VERSION 5.7 ;
BUSBITCHARS "[]" ;
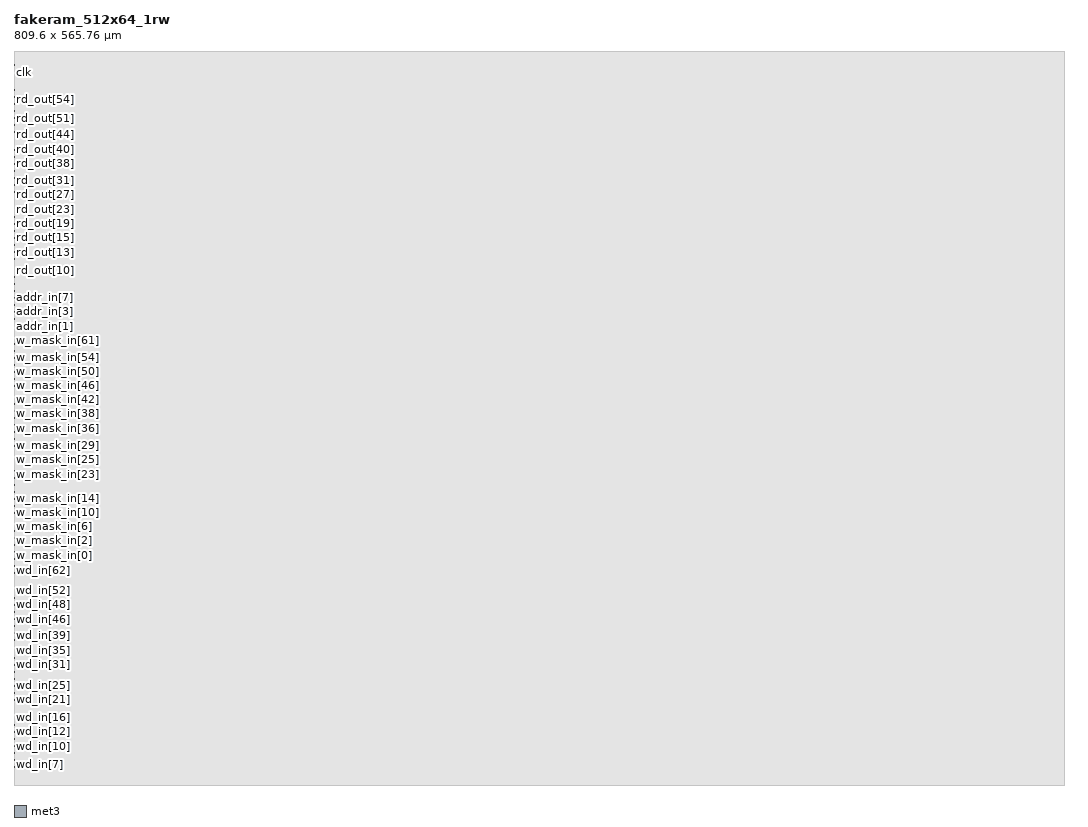
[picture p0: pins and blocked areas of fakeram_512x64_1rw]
MACRO fakeram_512x64_1rw
  FOREIGN fakeram_512x64_1rw 0 0 ;
  SYMMETRY X Y R90 ;
  SIZE 809.600 BY 565.760 ;
  CLASS BLOCK ;
  PIN wd_in[0]
    DIRECTION INPUT ;
    USE SIGNAL ;
    SHAPE ABUTMENT ;
    PORT
      LAYER met3 ;
      RECT 0.000 2.720 0.300 3.020 ;
    END
  END wd_in[0]
  PIN wd_in[1]
    DIRECTION INPUT ;
    USE SIGNAL ;
    SHAPE ABUTMENT ;
    PORT
      LAYER met3 ;
      RECT 0.000 5.440 0.300 5.740 ;
    END
  END wd_in[1]
  PIN wd_in[2]
    DIRECTION INPUT ;
    USE SIGNAL ;
    SHAPE ABUTMENT ;
    PORT
      LAYER met3 ;
      RECT 0.000 8.160 0.300 8.460 ;
    END
  END wd_in[2]
  PIN wd_in[3]
    DIRECTION INPUT ;
    USE SIGNAL ;
    SHAPE ABUTMENT ;
    PORT
      LAYER met3 ;
      RECT 0.000 10.880 0.300 11.180 ;
    END
  END wd_in[3]
  PIN wd_in[4]
    DIRECTION INPUT ;
    USE SIGNAL ;
    SHAPE ABUTMENT ;
    PORT
      LAYER met3 ;
      RECT 0.000 13.600 0.300 13.900 ;
    END
  END wd_in[4]
  PIN wd_in[5]
    DIRECTION INPUT ;
    USE SIGNAL ;
    SHAPE ABUTMENT ;
    PORT
      LAYER met3 ;
      RECT 0.000 16.320 0.300 16.620 ;
    END
  END wd_in[5]
  PIN wd_in[6]
    DIRECTION INPUT ;
    USE SIGNAL ;
    SHAPE ABUTMENT ;
    PORT
      LAYER met3 ;
      RECT 0.000 19.040 0.300 19.340 ;
    END
  END wd_in[6]
  PIN wd_in[7]
    DIRECTION INPUT ;
    USE SIGNAL ;
    SHAPE ABUTMENT ;
    PORT
      LAYER met3 ;
      RECT 0.000 21.760 0.300 22.060 ;
    END
  END wd_in[7]
  PIN wd_in[8]
    DIRECTION INPUT ;
    USE SIGNAL ;
    SHAPE ABUTMENT ;
    PORT
      LAYER met3 ;
      RECT 0.000 24.480 0.300 24.780 ;
    END
  END wd_in[8]
  PIN wd_in[9]
    DIRECTION INPUT ;
    USE SIGNAL ;
    SHAPE ABUTMENT ;
    PORT
      LAYER met3 ;
      RECT 0.000 27.200 0.300 27.500 ;
    END
  END wd_in[9]
  PIN wd_in[10]
    DIRECTION INPUT ;
    USE SIGNAL ;
    SHAPE ABUTMENT ;
    PORT
      LAYER met3 ;
      RECT 0.000 29.920 0.300 30.220 ;
    END
  END wd_in[10]
  PIN wd_in[11]
    DIRECTION INPUT ;
    USE SIGNAL ;
    SHAPE ABUTMENT ;
    PORT
      LAYER met3 ;
      RECT 0.000 32.640 0.300 32.940 ;
    END
  END wd_in[11]
  PIN wd_in[12]
    DIRECTION INPUT ;
    USE SIGNAL ;
    SHAPE ABUTMENT ;
    PORT
      LAYER met3 ;
      RECT 0.000 35.360 0.300 35.660 ;
    END
  END wd_in[12]
  PIN wd_in[13]
    DIRECTION INPUT ;
    USE SIGNAL ;
    SHAPE ABUTMENT ;
    PORT
      LAYER met3 ;
      RECT 0.000 38.080 0.300 38.380 ;
    END
  END wd_in[13]
  PIN wd_in[14]
    DIRECTION INPUT ;
    USE SIGNAL ;
    SHAPE ABUTMENT ;
    PORT
      LAYER met3 ;
      RECT 0.000 40.800 0.300 41.100 ;
    END
  END wd_in[14]
  PIN wd_in[15]
    DIRECTION INPUT ;
    USE SIGNAL ;
    SHAPE ABUTMENT ;
    PORT
      LAYER met3 ;
      RECT 0.000 43.520 0.300 43.820 ;
    END
  END wd_in[15]
  PIN wd_in[16]
    DIRECTION INPUT ;
    USE SIGNAL ;
    SHAPE ABUTMENT ;
    PORT
      LAYER met3 ;
      RECT 0.000 46.240 0.300 46.540 ;
    END
  END wd_in[16]
  PIN wd_in[17]
    DIRECTION INPUT ;
    USE SIGNAL ;
    SHAPE ABUTMENT ;
    PORT
      LAYER met3 ;
      RECT 0.000 48.960 0.300 49.260 ;
    END
  END wd_in[17]
  PIN wd_in[18]
    DIRECTION INPUT ;
    USE SIGNAL ;
    SHAPE ABUTMENT ;
    PORT
      LAYER met3 ;
      RECT 0.000 51.680 0.300 51.980 ;
    END
  END wd_in[18]
  PIN wd_in[19]
    DIRECTION INPUT ;
    USE SIGNAL ;
    SHAPE ABUTMENT ;
    PORT
      LAYER met3 ;
      RECT 0.000 54.400 0.300 54.700 ;
    END
  END wd_in[19]
  PIN wd_in[20]
    DIRECTION INPUT ;
    USE SIGNAL ;
    SHAPE ABUTMENT ;
    PORT
      LAYER met3 ;
      RECT 0.000 57.120 0.300 57.420 ;
    END
  END wd_in[20]
  PIN wd_in[21]
    DIRECTION INPUT ;
    USE SIGNAL ;
    SHAPE ABUTMENT ;
    PORT
      LAYER met3 ;
      RECT 0.000 59.840 0.300 60.140 ;
    END
  END wd_in[21]
  PIN wd_in[22]
    DIRECTION INPUT ;
    USE SIGNAL ;
    SHAPE ABUTMENT ;
    PORT
      LAYER met3 ;
      RECT 0.000 62.560 0.300 62.860 ;
    END
  END wd_in[22]
  PIN wd_in[23]
    DIRECTION INPUT ;
    USE SIGNAL ;
    SHAPE ABUTMENT ;
    PORT
      LAYER met3 ;
      RECT 0.000 65.280 0.300 65.580 ;
    END
  END wd_in[23]
  PIN wd_in[24]
    DIRECTION INPUT ;
    USE SIGNAL ;
    SHAPE ABUTMENT ;
    PORT
      LAYER met3 ;
      RECT 0.000 68.000 0.300 68.300 ;
    END
  END wd_in[24]
  PIN wd_in[25]
    DIRECTION INPUT ;
    USE SIGNAL ;
    SHAPE ABUTMENT ;
    PORT
      LAYER met3 ;
      RECT 0.000 70.720 0.300 71.020 ;
    END
  END wd_in[25]
  PIN wd_in[26]
    DIRECTION INPUT ;
    USE SIGNAL ;
    SHAPE ABUTMENT ;
    PORT
      LAYER met3 ;
      RECT 0.000 73.440 0.300 73.740 ;
    END
  END wd_in[26]
  PIN wd_in[27]
    DIRECTION INPUT ;
    USE SIGNAL ;
    SHAPE ABUTMENT ;
    PORT
      LAYER met3 ;
      RECT 0.000 76.160 0.300 76.460 ;
    END
  END wd_in[27]
  PIN wd_in[28]
    DIRECTION INPUT ;
    USE SIGNAL ;
    SHAPE ABUTMENT ;
    PORT
      LAYER met3 ;
      RECT 0.000 78.880 0.300 79.180 ;
    END
  END wd_in[28]
  PIN wd_in[29]
    DIRECTION INPUT ;
    USE SIGNAL ;
    SHAPE ABUTMENT ;
    PORT
      LAYER met3 ;
      RECT 0.000 81.600 0.300 81.900 ;
    END
  END wd_in[29]
  PIN wd_in[30]
    DIRECTION INPUT ;
    USE SIGNAL ;
    SHAPE ABUTMENT ;
    PORT
      LAYER met3 ;
      RECT 0.000 84.320 0.300 84.620 ;
    END
  END wd_in[30]
  PIN wd_in[31]
    DIRECTION INPUT ;
    USE SIGNAL ;
    SHAPE ABUTMENT ;
    PORT
      LAYER met3 ;
      RECT 0.000 87.040 0.300 87.340 ;
    END
  END wd_in[31]
  PIN wd_in[32]
    DIRECTION INPUT ;
    USE SIGNAL ;
    SHAPE ABUTMENT ;
    PORT
      LAYER met3 ;
      RECT 0.000 89.760 0.300 90.060 ;
    END
  END wd_in[32]
  PIN wd_in[33]
    DIRECTION INPUT ;
    USE SIGNAL ;
    SHAPE ABUTMENT ;
    PORT
      LAYER met3 ;
      RECT 0.000 92.480 0.300 92.780 ;
    END
  END wd_in[33]
  PIN wd_in[34]
    DIRECTION INPUT ;
    USE SIGNAL ;
    SHAPE ABUTMENT ;
    PORT
      LAYER met3 ;
      RECT 0.000 95.200 0.300 95.500 ;
    END
  END wd_in[34]
  PIN wd_in[35]
    DIRECTION INPUT ;
    USE SIGNAL ;
    SHAPE ABUTMENT ;
    PORT
      LAYER met3 ;
      RECT 0.000 97.920 0.300 98.220 ;
    END
  END wd_in[35]
  PIN wd_in[36]
    DIRECTION INPUT ;
    USE SIGNAL ;
    SHAPE ABUTMENT ;
    PORT
      LAYER met3 ;
      RECT 0.000 100.640 0.300 100.940 ;
    END
  END wd_in[36]
  PIN wd_in[37]
    DIRECTION INPUT ;
    USE SIGNAL ;
    SHAPE ABUTMENT ;
    PORT
      LAYER met3 ;
      RECT 0.000 103.360 0.300 103.660 ;
    END
  END wd_in[37]
  PIN wd_in[38]
    DIRECTION INPUT ;
    USE SIGNAL ;
    SHAPE ABUTMENT ;
    PORT
      LAYER met3 ;
      RECT 0.000 106.080 0.300 106.380 ;
    END
  END wd_in[38]
  PIN wd_in[39]
    DIRECTION INPUT ;
    USE SIGNAL ;
    SHAPE ABUTMENT ;
    PORT
      LAYER met3 ;
      RECT 0.000 108.800 0.300 109.100 ;
    END
  END wd_in[39]
  PIN wd_in[40]
    DIRECTION INPUT ;
    USE SIGNAL ;
    SHAPE ABUTMENT ;
    PORT
      LAYER met3 ;
      RECT 0.000 111.520 0.300 111.820 ;
    END
  END wd_in[40]
  PIN wd_in[41]
    DIRECTION INPUT ;
    USE SIGNAL ;
    SHAPE ABUTMENT ;
    PORT
      LAYER met3 ;
      RECT 0.000 114.240 0.300 114.540 ;
    END
  END wd_in[41]
  PIN wd_in[42]
    DIRECTION INPUT ;
    USE SIGNAL ;
    SHAPE ABUTMENT ;
    PORT
      LAYER met3 ;
      RECT 0.000 116.960 0.300 117.260 ;
    END
  END wd_in[42]
  PIN wd_in[43]
    DIRECTION INPUT ;
    USE SIGNAL ;
    SHAPE ABUTMENT ;
    PORT
      LAYER met3 ;
      RECT 0.000 119.680 0.300 119.980 ;
    END
  END wd_in[43]
  PIN wd_in[44]
    DIRECTION INPUT ;
    USE SIGNAL ;
    SHAPE ABUTMENT ;
    PORT
      LAYER met3 ;
      RECT 0.000 122.400 0.300 122.700 ;
    END
  END wd_in[44]
  PIN wd_in[45]
    DIRECTION INPUT ;
    USE SIGNAL ;
    SHAPE ABUTMENT ;
    PORT
      LAYER met3 ;
      RECT 0.000 125.120 0.300 125.420 ;
    END
  END wd_in[45]
  PIN wd_in[46]
    DIRECTION INPUT ;
    USE SIGNAL ;
    SHAPE ABUTMENT ;
    PORT
      LAYER met3 ;
      RECT 0.000 127.840 0.300 128.140 ;
    END
  END wd_in[46]
  PIN wd_in[47]
    DIRECTION INPUT ;
    USE SIGNAL ;
    SHAPE ABUTMENT ;
    PORT
      LAYER met3 ;
      RECT 0.000 130.560 0.300 130.860 ;
    END
  END wd_in[47]
  PIN wd_in[48]
    DIRECTION INPUT ;
    USE SIGNAL ;
    SHAPE ABUTMENT ;
    PORT
      LAYER met3 ;
      RECT 0.000 133.280 0.300 133.580 ;
    END
  END wd_in[48]
  PIN wd_in[49]
    DIRECTION INPUT ;
    USE SIGNAL ;
    SHAPE ABUTMENT ;
    PORT
      LAYER met3 ;
      RECT 0.000 136.000 0.300 136.300 ;
    END
  END wd_in[49]
  PIN wd_in[50]
    DIRECTION INPUT ;
    USE SIGNAL ;
    SHAPE ABUTMENT ;
    PORT
      LAYER met3 ;
      RECT 0.000 138.720 0.300 139.020 ;
    END
  END wd_in[50]
  PIN wd_in[51]
    DIRECTION INPUT ;
    USE SIGNAL ;
    SHAPE ABUTMENT ;
    PORT
      LAYER met3 ;
      RECT 0.000 141.440 0.300 141.740 ;
    END
  END wd_in[51]
  PIN wd_in[52]
    DIRECTION INPUT ;
    USE SIGNAL ;
    SHAPE ABUTMENT ;
    PORT
      LAYER met3 ;
      RECT 0.000 144.160 0.300 144.460 ;
    END
  END wd_in[52]
  PIN wd_in[53]
    DIRECTION INPUT ;
    USE SIGNAL ;
    SHAPE ABUTMENT ;
    PORT
      LAYER met3 ;
      RECT 0.000 146.880 0.300 147.180 ;
    END
  END wd_in[53]
  PIN wd_in[54]
    DIRECTION INPUT ;
    USE SIGNAL ;
    SHAPE ABUTMENT ;
    PORT
      LAYER met3 ;
      RECT 0.000 149.600 0.300 149.900 ;
    END
  END wd_in[54]
  PIN wd_in[55]
    DIRECTION INPUT ;
    USE SIGNAL ;
    SHAPE ABUTMENT ;
    PORT
      LAYER met3 ;
      RECT 0.000 152.320 0.300 152.620 ;
    END
  END wd_in[55]
  PIN wd_in[56]
    DIRECTION INPUT ;
    USE SIGNAL ;
    SHAPE ABUTMENT ;
    PORT
      LAYER met3 ;
      RECT 0.000 155.040 0.300 155.340 ;
    END
  END wd_in[56]
  PIN wd_in[57]
    DIRECTION INPUT ;
    USE SIGNAL ;
    SHAPE ABUTMENT ;
    PORT
      LAYER met3 ;
      RECT 0.000 157.760 0.300 158.060 ;
    END
  END wd_in[57]
  PIN wd_in[58]
    DIRECTION INPUT ;
    USE SIGNAL ;
    SHAPE ABUTMENT ;
    PORT
      LAYER met3 ;
      RECT 0.000 160.480 0.300 160.780 ;
    END
  END wd_in[58]
  PIN wd_in[59]
    DIRECTION INPUT ;
    USE SIGNAL ;
    SHAPE ABUTMENT ;
    PORT
      LAYER met3 ;
      RECT 0.000 163.200 0.300 163.500 ;
    END
  END wd_in[59]
  PIN wd_in[60]
    DIRECTION INPUT ;
    USE SIGNAL ;
    SHAPE ABUTMENT ;
    PORT
      LAYER met3 ;
      RECT 0.000 165.920 0.300 166.220 ;
    END
  END wd_in[60]
  PIN wd_in[61]
    DIRECTION INPUT ;
    USE SIGNAL ;
    SHAPE ABUTMENT ;
    PORT
      LAYER met3 ;
      RECT 0.000 168.640 0.300 168.940 ;
    END
  END wd_in[61]
  PIN wd_in[62]
    DIRECTION INPUT ;
    USE SIGNAL ;
    SHAPE ABUTMENT ;
    PORT
      LAYER met3 ;
      RECT 0.000 171.360 0.300 171.660 ;
    END
  END wd_in[62]
  PIN wd_in[63]
    DIRECTION INPUT ;
    USE SIGNAL ;
    SHAPE ABUTMENT ;
    PORT
      LAYER met3 ;
      RECT 0.000 174.080 0.300 174.380 ;
    END
  END wd_in[63]
  PIN w_mask_in[0]
    DIRECTION INPUT ;
    USE SIGNAL ;
    SHAPE ABUTMENT ;
    PORT
      LAYER met3 ;
      RECT 0.000 176.800 0.300 177.100 ;
    END
  END w_mask_in[0]
  PIN w_mask_in[1]
    DIRECTION INPUT ;
    USE SIGNAL ;
    SHAPE ABUTMENT ;
    PORT
      LAYER met3 ;
      RECT 0.000 179.520 0.300 179.820 ;
    END
  END w_mask_in[1]
  PIN w_mask_in[2]
    DIRECTION INPUT ;
    USE SIGNAL ;
    SHAPE ABUTMENT ;
    PORT
      LAYER met3 ;
      RECT 0.000 182.240 0.300 182.540 ;
    END
  END w_mask_in[2]
  PIN w_mask_in[3]
    DIRECTION INPUT ;
    USE SIGNAL ;
    SHAPE ABUTMENT ;
    PORT
      LAYER met3 ;
      RECT 0.000 184.960 0.300 185.260 ;
    END
  END w_mask_in[3]
  PIN w_mask_in[4]
    DIRECTION INPUT ;
    USE SIGNAL ;
    SHAPE ABUTMENT ;
    PORT
      LAYER met3 ;
      RECT 0.000 187.680 0.300 187.980 ;
    END
  END w_mask_in[4]
  PIN w_mask_in[5]
    DIRECTION INPUT ;
    USE SIGNAL ;
    SHAPE ABUTMENT ;
    PORT
      LAYER met3 ;
      RECT 0.000 190.400 0.300 190.700 ;
    END
  END w_mask_in[5]
  PIN w_mask_in[6]
    DIRECTION INPUT ;
    USE SIGNAL ;
    SHAPE ABUTMENT ;
    PORT
      LAYER met3 ;
      RECT 0.000 193.120 0.300 193.420 ;
    END
  END w_mask_in[6]
  PIN w_mask_in[7]
    DIRECTION INPUT ;
    USE SIGNAL ;
    SHAPE ABUTMENT ;
    PORT
      LAYER met3 ;
      RECT 0.000 195.840 0.300 196.140 ;
    END
  END w_mask_in[7]
  PIN w_mask_in[8]
    DIRECTION INPUT ;
    USE SIGNAL ;
    SHAPE ABUTMENT ;
    PORT
      LAYER met3 ;
      RECT 0.000 198.560 0.300 198.860 ;
    END
  END w_mask_in[8]
  PIN w_mask_in[9]
    DIRECTION INPUT ;
    USE SIGNAL ;
    SHAPE ABUTMENT ;
    PORT
      LAYER met3 ;
      RECT 0.000 201.280 0.300 201.580 ;
    END
  END w_mask_in[9]
  PIN w_mask_in[10]
    DIRECTION INPUT ;
    USE SIGNAL ;
    SHAPE ABUTMENT ;
    PORT
      LAYER met3 ;
      RECT 0.000 204.000 0.300 204.300 ;
    END
  END w_mask_in[10]
  PIN w_mask_in[11]
    DIRECTION INPUT ;
    USE SIGNAL ;
    SHAPE ABUTMENT ;
    PORT
      LAYER met3 ;
      RECT 0.000 206.720 0.300 207.020 ;
    END
  END w_mask_in[11]
  PIN w_mask_in[12]
    DIRECTION INPUT ;
    USE SIGNAL ;
    SHAPE ABUTMENT ;
    PORT
      LAYER met3 ;
      RECT 0.000 209.440 0.300 209.740 ;
    END
  END w_mask_in[12]
  PIN w_mask_in[13]
    DIRECTION INPUT ;
    USE SIGNAL ;
    SHAPE ABUTMENT ;
    PORT
      LAYER met3 ;
      RECT 0.000 212.160 0.300 212.460 ;
    END
  END w_mask_in[13]
  PIN w_mask_in[14]
    DIRECTION INPUT ;
    USE SIGNAL ;
    SHAPE ABUTMENT ;
    PORT
      LAYER met3 ;
      RECT 0.000 214.880 0.300 215.180 ;
    END
  END w_mask_in[14]
  PIN w_mask_in[15]
    DIRECTION INPUT ;
    USE SIGNAL ;
    SHAPE ABUTMENT ;
    PORT
      LAYER met3 ;
      RECT 0.000 217.600 0.300 217.900 ;
    END
  END w_mask_in[15]
  PIN w_mask_in[16]
    DIRECTION INPUT ;
    USE SIGNAL ;
    SHAPE ABUTMENT ;
    PORT
      LAYER met3 ;
      RECT 0.000 220.320 0.300 220.620 ;
    END
  END w_mask_in[16]
  PIN w_mask_in[17]
    DIRECTION INPUT ;
    USE SIGNAL ;
    SHAPE ABUTMENT ;
    PORT
      LAYER met3 ;
      RECT 0.000 223.040 0.300 223.340 ;
    END
  END w_mask_in[17]
  PIN w_mask_in[18]
    DIRECTION INPUT ;
    USE SIGNAL ;
    SHAPE ABUTMENT ;
    PORT
      LAYER met3 ;
      RECT 0.000 225.760 0.300 226.060 ;
    END
  END w_mask_in[18]
  PIN w_mask_in[19]
    DIRECTION INPUT ;
    USE SIGNAL ;
    SHAPE ABUTMENT ;
    PORT
      LAYER met3 ;
      RECT 0.000 228.480 0.300 228.780 ;
    END
  END w_mask_in[19]
  PIN w_mask_in[20]
    DIRECTION INPUT ;
    USE SIGNAL ;
    SHAPE ABUTMENT ;
    PORT
      LAYER met3 ;
      RECT 0.000 231.200 0.300 231.500 ;
    END
  END w_mask_in[20]
  PIN w_mask_in[21]
    DIRECTION INPUT ;
    USE SIGNAL ;
    SHAPE ABUTMENT ;
    PORT
      LAYER met3 ;
      RECT 0.000 233.920 0.300 234.220 ;
    END
  END w_mask_in[21]
  PIN w_mask_in[22]
    DIRECTION INPUT ;
    USE SIGNAL ;
    SHAPE ABUTMENT ;
    PORT
      LAYER met3 ;
      RECT 0.000 236.640 0.300 236.940 ;
    END
  END w_mask_in[22]
  PIN w_mask_in[23]
    DIRECTION INPUT ;
    USE SIGNAL ;
    SHAPE ABUTMENT ;
    PORT
      LAYER met3 ;
      RECT 0.000 239.360 0.300 239.660 ;
    END
  END w_mask_in[23]
  PIN w_mask_in[24]
    DIRECTION INPUT ;
    USE SIGNAL ;
    SHAPE ABUTMENT ;
    PORT
      LAYER met3 ;
      RECT 0.000 242.080 0.300 242.380 ;
    END
  END w_mask_in[24]
  PIN w_mask_in[25]
    DIRECTION INPUT ;
    USE SIGNAL ;
    SHAPE ABUTMENT ;
    PORT
      LAYER met3 ;
      RECT 0.000 244.800 0.300 245.100 ;
    END
  END w_mask_in[25]
  PIN w_mask_in[26]
    DIRECTION INPUT ;
    USE SIGNAL ;
    SHAPE ABUTMENT ;
    PORT
      LAYER met3 ;
      RECT 0.000 247.520 0.300 247.820 ;
    END
  END w_mask_in[26]
  PIN w_mask_in[27]
    DIRECTION INPUT ;
    USE SIGNAL ;
    SHAPE ABUTMENT ;
    PORT
      LAYER met3 ;
      RECT 0.000 250.240 0.300 250.540 ;
    END
  END w_mask_in[27]
  PIN w_mask_in[28]
    DIRECTION INPUT ;
    USE SIGNAL ;
    SHAPE ABUTMENT ;
    PORT
      LAYER met3 ;
      RECT 0.000 252.960 0.300 253.260 ;
    END
  END w_mask_in[28]
  PIN w_mask_in[29]
    DIRECTION INPUT ;
    USE SIGNAL ;
    SHAPE ABUTMENT ;
    PORT
      LAYER met3 ;
      RECT 0.000 255.680 0.300 255.980 ;
    END
  END w_mask_in[29]
  PIN w_mask_in[30]
    DIRECTION INPUT ;
    USE SIGNAL ;
    SHAPE ABUTMENT ;
    PORT
      LAYER met3 ;
      RECT 0.000 258.400 0.300 258.700 ;
    END
  END w_mask_in[30]
  PIN w_mask_in[31]
    DIRECTION INPUT ;
    USE SIGNAL ;
    SHAPE ABUTMENT ;
    PORT
      LAYER met3 ;
      RECT 0.000 261.120 0.300 261.420 ;
    END
  END w_mask_in[31]
  PIN w_mask_in[32]
    DIRECTION INPUT ;
    USE SIGNAL ;
    SHAPE ABUTMENT ;
    PORT
      LAYER met3 ;
      RECT 0.000 263.840 0.300 264.140 ;
    END
  END w_mask_in[32]
  PIN w_mask_in[33]
    DIRECTION INPUT ;
    USE SIGNAL ;
    SHAPE ABUTMENT ;
    PORT
      LAYER met3 ;
      RECT 0.000 266.560 0.300 266.860 ;
    END
  END w_mask_in[33]
  PIN w_mask_in[34]
    DIRECTION INPUT ;
    USE SIGNAL ;
    SHAPE ABUTMENT ;
    PORT
      LAYER met3 ;
      RECT 0.000 269.280 0.300 269.580 ;
    END
  END w_mask_in[34]
  PIN w_mask_in[35]
    DIRECTION INPUT ;
    USE SIGNAL ;
    SHAPE ABUTMENT ;
    PORT
      LAYER met3 ;
      RECT 0.000 272.000 0.300 272.300 ;
    END
  END w_mask_in[35]
  PIN w_mask_in[36]
    DIRECTION INPUT ;
    USE SIGNAL ;
    SHAPE ABUTMENT ;
    PORT
      LAYER met3 ;
      RECT 0.000 274.720 0.300 275.020 ;
    END
  END w_mask_in[36]
  PIN w_mask_in[37]
    DIRECTION INPUT ;
    USE SIGNAL ;
    SHAPE ABUTMENT ;
    PORT
      LAYER met3 ;
      RECT 0.000 277.440 0.300 277.740 ;
    END
  END w_mask_in[37]
  PIN w_mask_in[38]
    DIRECTION INPUT ;
    USE SIGNAL ;
    SHAPE ABUTMENT ;
    PORT
      LAYER met3 ;
      RECT 0.000 280.160 0.300 280.460 ;
    END
  END w_mask_in[38]
  PIN w_mask_in[39]
    DIRECTION INPUT ;
    USE SIGNAL ;
    SHAPE ABUTMENT ;
    PORT
      LAYER met3 ;
      RECT 0.000 282.880 0.300 283.180 ;
    END
  END w_mask_in[39]
  PIN w_mask_in[40]
    DIRECTION INPUT ;
    USE SIGNAL ;
    SHAPE ABUTMENT ;
    PORT
      LAYER met3 ;
      RECT 0.000 285.600 0.300 285.900 ;
    END
  END w_mask_in[40]
  PIN w_mask_in[41]
    DIRECTION INPUT ;
    USE SIGNAL ;
    SHAPE ABUTMENT ;
    PORT
      LAYER met3 ;
      RECT 0.000 288.320 0.300 288.620 ;
    END
  END w_mask_in[41]
  PIN w_mask_in[42]
    DIRECTION INPUT ;
    USE SIGNAL ;
    SHAPE ABUTMENT ;
    PORT
      LAYER met3 ;
      RECT 0.000 291.040 0.300 291.340 ;
    END
  END w_mask_in[42]
  PIN w_mask_in[43]
    DIRECTION INPUT ;
    USE SIGNAL ;
    SHAPE ABUTMENT ;
    PORT
      LAYER met3 ;
      RECT 0.000 293.760 0.300 294.060 ;
    END
  END w_mask_in[43]
  PIN w_mask_in[44]
    DIRECTION INPUT ;
    USE SIGNAL ;
    SHAPE ABUTMENT ;
    PORT
      LAYER met3 ;
      RECT 0.000 296.480 0.300 296.780 ;
    END
  END w_mask_in[44]
  PIN w_mask_in[45]
    DIRECTION INPUT ;
    USE SIGNAL ;
    SHAPE ABUTMENT ;
    PORT
      LAYER met3 ;
      RECT 0.000 299.200 0.300 299.500 ;
    END
  END w_mask_in[45]
  PIN w_mask_in[46]
    DIRECTION INPUT ;
    USE SIGNAL ;
    SHAPE ABUTMENT ;
    PORT
      LAYER met3 ;
      RECT 0.000 301.920 0.300 302.220 ;
    END
  END w_mask_in[46]
  PIN w_mask_in[47]
    DIRECTION INPUT ;
    USE SIGNAL ;
    SHAPE ABUTMENT ;
    PORT
      LAYER met3 ;
      RECT 0.000 304.640 0.300 304.940 ;
    END
  END w_mask_in[47]
  PIN w_mask_in[48]
    DIRECTION INPUT ;
    USE SIGNAL ;
    SHAPE ABUTMENT ;
    PORT
      LAYER met3 ;
      RECT 0.000 307.360 0.300 307.660 ;
    END
  END w_mask_in[48]
  PIN w_mask_in[49]
    DIRECTION INPUT ;
    USE SIGNAL ;
    SHAPE ABUTMENT ;
    PORT
      LAYER met3 ;
      RECT 0.000 310.080 0.300 310.380 ;
    END
  END w_mask_in[49]
  PIN w_mask_in[50]
    DIRECTION INPUT ;
    USE SIGNAL ;
    SHAPE ABUTMENT ;
    PORT
      LAYER met3 ;
      RECT 0.000 312.800 0.300 313.100 ;
    END
  END w_mask_in[50]
  PIN w_mask_in[51]
    DIRECTION INPUT ;
    USE SIGNAL ;
    SHAPE ABUTMENT ;
    PORT
      LAYER met3 ;
      RECT 0.000 315.520 0.300 315.820 ;
    END
  END w_mask_in[51]
  PIN w_mask_in[52]
    DIRECTION INPUT ;
    USE SIGNAL ;
    SHAPE ABUTMENT ;
    PORT
      LAYER met3 ;
      RECT 0.000 318.240 0.300 318.540 ;
    END
  END w_mask_in[52]
  PIN w_mask_in[53]
    DIRECTION INPUT ;
    USE SIGNAL ;
    SHAPE ABUTMENT ;
    PORT
      LAYER met3 ;
      RECT 0.000 320.960 0.300 321.260 ;
    END
  END w_mask_in[53]
  PIN w_mask_in[54]
    DIRECTION INPUT ;
    USE SIGNAL ;
    SHAPE ABUTMENT ;
    PORT
      LAYER met3 ;
      RECT 0.000 323.680 0.300 323.980 ;
    END
  END w_mask_in[54]
  PIN w_mask_in[55]
    DIRECTION INPUT ;
    USE SIGNAL ;
    SHAPE ABUTMENT ;
    PORT
      LAYER met3 ;
      RECT 0.000 326.400 0.300 326.700 ;
    END
  END w_mask_in[55]
  PIN w_mask_in[56]
    DIRECTION INPUT ;
    USE SIGNAL ;
    SHAPE ABUTMENT ;
    PORT
      LAYER met3 ;
      RECT 0.000 329.120 0.300 329.420 ;
    END
  END w_mask_in[56]
  PIN w_mask_in[57]
    DIRECTION INPUT ;
    USE SIGNAL ;
    SHAPE ABUTMENT ;
    PORT
      LAYER met3 ;
      RECT 0.000 331.840 0.300 332.140 ;
    END
  END w_mask_in[57]
  PIN w_mask_in[58]
    DIRECTION INPUT ;
    USE SIGNAL ;
    SHAPE ABUTMENT ;
    PORT
      LAYER met3 ;
      RECT 0.000 334.560 0.300 334.860 ;
    END
  END w_mask_in[58]
  PIN w_mask_in[59]
    DIRECTION INPUT ;
    USE SIGNAL ;
    SHAPE ABUTMENT ;
    PORT
      LAYER met3 ;
      RECT 0.000 337.280 0.300 337.580 ;
    END
  END w_mask_in[59]
  PIN w_mask_in[60]
    DIRECTION INPUT ;
    USE SIGNAL ;
    SHAPE ABUTMENT ;
    PORT
      LAYER met3 ;
      RECT 0.000 340.000 0.300 340.300 ;
    END
  END w_mask_in[60]
  PIN w_mask_in[61]
    DIRECTION INPUT ;
    USE SIGNAL ;
    SHAPE ABUTMENT ;
    PORT
      LAYER met3 ;
      RECT 0.000 342.720 0.300 343.020 ;
    END
  END w_mask_in[61]
  PIN w_mask_in[62]
    DIRECTION INPUT ;
    USE SIGNAL ;
    SHAPE ABUTMENT ;
    PORT
      LAYER met3 ;
      RECT 0.000 345.440 0.300 345.740 ;
    END
  END w_mask_in[62]
  PIN w_mask_in[63]
    DIRECTION INPUT ;
    USE SIGNAL ;
    SHAPE ABUTMENT ;
    PORT
      LAYER met3 ;
      RECT 0.000 348.160 0.300 348.460 ;
    END
  END w_mask_in[63]
  PIN addr_in[0]
    DIRECTION INPUT ;
    USE SIGNAL ;
    SHAPE ABUTMENT ;
    PORT
      LAYER met3 ;
      RECT 0.000 350.880 0.300 351.180 ;
    END
  END addr_in[0]
  PIN addr_in[1]
    DIRECTION INPUT ;
    USE SIGNAL ;
    SHAPE ABUTMENT ;
    PORT
      LAYER met3 ;
      RECT 0.000 353.600 0.300 353.900 ;
    END
  END addr_in[1]
  PIN addr_in[2]
    DIRECTION INPUT ;
    USE SIGNAL ;
    SHAPE ABUTMENT ;
    PORT
      LAYER met3 ;
      RECT 0.000 356.320 0.300 356.620 ;
    END
  END addr_in[2]
  PIN addr_in[3]
    DIRECTION INPUT ;
    USE SIGNAL ;
    SHAPE ABUTMENT ;
    PORT
      LAYER met3 ;
      RECT 0.000 359.040 0.300 359.340 ;
    END
  END addr_in[3]
  PIN addr_in[4]
    DIRECTION INPUT ;
    USE SIGNAL ;
    SHAPE ABUTMENT ;
    PORT
      LAYER met3 ;
      RECT 0.000 361.760 0.300 362.060 ;
    END
  END addr_in[4]
  PIN addr_in[5]
    DIRECTION INPUT ;
    USE SIGNAL ;
    SHAPE ABUTMENT ;
    PORT
      LAYER met3 ;
      RECT 0.000 364.480 0.300 364.780 ;
    END
  END addr_in[5]
  PIN addr_in[6]
    DIRECTION INPUT ;
    USE SIGNAL ;
    SHAPE ABUTMENT ;
    PORT
      LAYER met3 ;
      RECT 0.000 367.200 0.300 367.500 ;
    END
  END addr_in[6]
  PIN addr_in[7]
    DIRECTION INPUT ;
    USE SIGNAL ;
    SHAPE ABUTMENT ;
    PORT
      LAYER met3 ;
      RECT 0.000 369.920 0.300 370.220 ;
    END
  END addr_in[7]
  PIN addr_in[8]
    DIRECTION INPUT ;
    USE SIGNAL ;
    SHAPE ABUTMENT ;
    PORT
      LAYER met3 ;
      RECT 0.000 372.640 0.300 372.940 ;
    END
  END addr_in[8]
  PIN rd_out[0]
    DIRECTION OUTPUT ;
    USE SIGNAL ;
    SHAPE ABUTMENT ;
    PORT
      LAYER met3 ;
      RECT 0.000 375.360 0.300 375.660 ;
    END
  END rd_out[0]
  PIN rd_out[1]
    DIRECTION OUTPUT ;
    USE SIGNAL ;
    SHAPE ABUTMENT ;
    PORT
      LAYER met3 ;
      RECT 0.000 378.080 0.300 378.380 ;
    END
  END rd_out[1]
  PIN rd_out[2]
    DIRECTION OUTPUT ;
    USE SIGNAL ;
    SHAPE ABUTMENT ;
    PORT
      LAYER met3 ;
      RECT 0.000 380.800 0.300 381.100 ;
    END
  END rd_out[2]
  PIN rd_out[3]
    DIRECTION OUTPUT ;
    USE SIGNAL ;
    SHAPE ABUTMENT ;
    PORT
      LAYER met3 ;
      RECT 0.000 383.520 0.300 383.820 ;
    END
  END rd_out[3]
  PIN rd_out[4]
    DIRECTION OUTPUT ;
    USE SIGNAL ;
    SHAPE ABUTMENT ;
    PORT
      LAYER met3 ;
      RECT 0.000 386.240 0.300 386.540 ;
    END
  END rd_out[4]
  PIN rd_out[5]
    DIRECTION OUTPUT ;
    USE SIGNAL ;
    SHAPE ABUTMENT ;
    PORT
      LAYER met3 ;
      RECT 0.000 388.960 0.300 389.260 ;
    END
  END rd_out[5]
  PIN rd_out[6]
    DIRECTION OUTPUT ;
    USE SIGNAL ;
    SHAPE ABUTMENT ;
    PORT
      LAYER met3 ;
      RECT 0.000 391.680 0.300 391.980 ;
    END
  END rd_out[6]
  PIN rd_out[7]
    DIRECTION OUTPUT ;
    USE SIGNAL ;
    SHAPE ABUTMENT ;
    PORT
      LAYER met3 ;
      RECT 0.000 394.400 0.300 394.700 ;
    END
  END rd_out[7]
  PIN rd_out[8]
    DIRECTION OUTPUT ;
    USE SIGNAL ;
    SHAPE ABUTMENT ;
    PORT
      LAYER met3 ;
      RECT 0.000 397.120 0.300 397.420 ;
    END
  END rd_out[8]
  PIN rd_out[9]
    DIRECTION OUTPUT ;
    USE SIGNAL ;
    SHAPE ABUTMENT ;
    PORT
      LAYER met3 ;
      RECT 0.000 399.840 0.300 400.140 ;
    END
  END rd_out[9]
  PIN rd_out[10]
    DIRECTION OUTPUT ;
    USE SIGNAL ;
    SHAPE ABUTMENT ;
    PORT
      LAYER met3 ;
      RECT 0.000 402.560 0.300 402.860 ;
    END
  END rd_out[10]
  PIN rd_out[11]
    DIRECTION OUTPUT ;
    USE SIGNAL ;
    SHAPE ABUTMENT ;
    PORT
      LAYER met3 ;
      RECT 0.000 405.280 0.300 405.580 ;
    END
  END rd_out[11]
  PIN rd_out[12]
    DIRECTION OUTPUT ;
    USE SIGNAL ;
    SHAPE ABUTMENT ;
    PORT
      LAYER met3 ;
      RECT 0.000 408.000 0.300 408.300 ;
    END
  END rd_out[12]
  PIN rd_out[13]
    DIRECTION OUTPUT ;
    USE SIGNAL ;
    SHAPE ABUTMENT ;
    PORT
      LAYER met3 ;
      RECT 0.000 410.720 0.300 411.020 ;
    END
  END rd_out[13]
  PIN rd_out[14]
    DIRECTION OUTPUT ;
    USE SIGNAL ;
    SHAPE ABUTMENT ;
    PORT
      LAYER met3 ;
      RECT 0.000 413.440 0.300 413.740 ;
    END
  END rd_out[14]
  PIN rd_out[15]
    DIRECTION OUTPUT ;
    USE SIGNAL ;
    SHAPE ABUTMENT ;
    PORT
      LAYER met3 ;
      RECT 0.000 416.160 0.300 416.460 ;
    END
  END rd_out[15]
  PIN rd_out[16]
    DIRECTION OUTPUT ;
    USE SIGNAL ;
    SHAPE ABUTMENT ;
    PORT
      LAYER met3 ;
      RECT 0.000 418.880 0.300 419.180 ;
    END
  END rd_out[16]
  PIN rd_out[17]
    DIRECTION OUTPUT ;
    USE SIGNAL ;
    SHAPE ABUTMENT ;
    PORT
      LAYER met3 ;
      RECT 0.000 421.600 0.300 421.900 ;
    END
  END rd_out[17]
  PIN rd_out[18]
    DIRECTION OUTPUT ;
    USE SIGNAL ;
    SHAPE ABUTMENT ;
    PORT
      LAYER met3 ;
      RECT 0.000 424.320 0.300 424.620 ;
    END
  END rd_out[18]
  PIN rd_out[19]
    DIRECTION OUTPUT ;
    USE SIGNAL ;
    SHAPE ABUTMENT ;
    PORT
      LAYER met3 ;
      RECT 0.000 427.040 0.300 427.340 ;
    END
  END rd_out[19]
  PIN rd_out[20]
    DIRECTION OUTPUT ;
    USE SIGNAL ;
    SHAPE ABUTMENT ;
    PORT
      LAYER met3 ;
      RECT 0.000 429.760 0.300 430.060 ;
    END
  END rd_out[20]
  PIN rd_out[21]
    DIRECTION OUTPUT ;
    USE SIGNAL ;
    SHAPE ABUTMENT ;
    PORT
      LAYER met3 ;
      RECT 0.000 432.480 0.300 432.780 ;
    END
  END rd_out[21]
  PIN rd_out[22]
    DIRECTION OUTPUT ;
    USE SIGNAL ;
    SHAPE ABUTMENT ;
    PORT
      LAYER met3 ;
      RECT 0.000 435.200 0.300 435.500 ;
    END
  END rd_out[22]
  PIN rd_out[23]
    DIRECTION OUTPUT ;
    USE SIGNAL ;
    SHAPE ABUTMENT ;
    PORT
      LAYER met3 ;
      RECT 0.000 437.920 0.300 438.220 ;
    END
  END rd_out[23]
  PIN rd_out[24]
    DIRECTION OUTPUT ;
    USE SIGNAL ;
    SHAPE ABUTMENT ;
    PORT
      LAYER met3 ;
      RECT 0.000 440.640 0.300 440.940 ;
    END
  END rd_out[24]
  PIN rd_out[25]
    DIRECTION OUTPUT ;
    USE SIGNAL ;
    SHAPE ABUTMENT ;
    PORT
      LAYER met3 ;
      RECT 0.000 443.360 0.300 443.660 ;
    END
  END rd_out[25]
  PIN rd_out[26]
    DIRECTION OUTPUT ;
    USE SIGNAL ;
    SHAPE ABUTMENT ;
    PORT
      LAYER met3 ;
      RECT 0.000 446.080 0.300 446.380 ;
    END
  END rd_out[26]
  PIN rd_out[27]
    DIRECTION OUTPUT ;
    USE SIGNAL ;
    SHAPE ABUTMENT ;
    PORT
      LAYER met3 ;
      RECT 0.000 448.800 0.300 449.100 ;
    END
  END rd_out[27]
  PIN rd_out[28]
    DIRECTION OUTPUT ;
    USE SIGNAL ;
    SHAPE ABUTMENT ;
    PORT
      LAYER met3 ;
      RECT 0.000 451.520 0.300 451.820 ;
    END
  END rd_out[28]
  PIN rd_out[29]
    DIRECTION OUTPUT ;
    USE SIGNAL ;
    SHAPE ABUTMENT ;
    PORT
      LAYER met3 ;
      RECT 0.000 454.240 0.300 454.540 ;
    END
  END rd_out[29]
  PIN rd_out[30]
    DIRECTION OUTPUT ;
    USE SIGNAL ;
    SHAPE ABUTMENT ;
    PORT
      LAYER met3 ;
      RECT 0.000 456.960 0.300 457.260 ;
    END
  END rd_out[30]
  PIN rd_out[31]
    DIRECTION OUTPUT ;
    USE SIGNAL ;
    SHAPE ABUTMENT ;
    PORT
      LAYER met3 ;
      RECT 0.000 459.680 0.300 459.980 ;
    END
  END rd_out[31]
  PIN rd_out[32]
    DIRECTION OUTPUT ;
    USE SIGNAL ;
    SHAPE ABUTMENT ;
    PORT
      LAYER met3 ;
      RECT 0.000 462.400 0.300 462.700 ;
    END
  END rd_out[32]
  PIN rd_out[33]
    DIRECTION OUTPUT ;
    USE SIGNAL ;
    SHAPE ABUTMENT ;
    PORT
      LAYER met3 ;
      RECT 0.000 465.120 0.300 465.420 ;
    END
  END rd_out[33]
  PIN rd_out[34]
    DIRECTION OUTPUT ;
    USE SIGNAL ;
    SHAPE ABUTMENT ;
    PORT
      LAYER met3 ;
      RECT 0.000 467.840 0.300 468.140 ;
    END
  END rd_out[34]
  PIN rd_out[35]
    DIRECTION OUTPUT ;
    USE SIGNAL ;
    SHAPE ABUTMENT ;
    PORT
      LAYER met3 ;
      RECT 0.000 470.560 0.300 470.860 ;
    END
  END rd_out[35]
  PIN rd_out[36]
    DIRECTION OUTPUT ;
    USE SIGNAL ;
    SHAPE ABUTMENT ;
    PORT
      LAYER met3 ;
      RECT 0.000 473.280 0.300 473.580 ;
    END
  END rd_out[36]
  PIN rd_out[37]
    DIRECTION OUTPUT ;
    USE SIGNAL ;
    SHAPE ABUTMENT ;
    PORT
      LAYER met3 ;
      RECT 0.000 476.000 0.300 476.300 ;
    END
  END rd_out[37]
  PIN rd_out[38]
    DIRECTION OUTPUT ;
    USE SIGNAL ;
    SHAPE ABUTMENT ;
    PORT
      LAYER met3 ;
      RECT 0.000 478.720 0.300 479.020 ;
    END
  END rd_out[38]
  PIN rd_out[39]
    DIRECTION OUTPUT ;
    USE SIGNAL ;
    SHAPE ABUTMENT ;
    PORT
      LAYER met3 ;
      RECT 0.000 481.440 0.300 481.740 ;
    END
  END rd_out[39]
  PIN rd_out[40]
    DIRECTION OUTPUT ;
    USE SIGNAL ;
    SHAPE ABUTMENT ;
    PORT
      LAYER met3 ;
      RECT 0.000 484.160 0.300 484.460 ;
    END
  END rd_out[40]
  PIN rd_out[41]
    DIRECTION OUTPUT ;
    USE SIGNAL ;
    SHAPE ABUTMENT ;
    PORT
      LAYER met3 ;
      RECT 0.000 486.880 0.300 487.180 ;
    END
  END rd_out[41]
  PIN rd_out[42]
    DIRECTION OUTPUT ;
    USE SIGNAL ;
    SHAPE ABUTMENT ;
    PORT
      LAYER met3 ;
      RECT 0.000 489.600 0.300 489.900 ;
    END
  END rd_out[42]
  PIN rd_out[43]
    DIRECTION OUTPUT ;
    USE SIGNAL ;
    SHAPE ABUTMENT ;
    PORT
      LAYER met3 ;
      RECT 0.000 492.320 0.300 492.620 ;
    END
  END rd_out[43]
  PIN rd_out[44]
    DIRECTION OUTPUT ;
    USE SIGNAL ;
    SHAPE ABUTMENT ;
    PORT
      LAYER met3 ;
      RECT 0.000 495.040 0.300 495.340 ;
    END
  END rd_out[44]
  PIN rd_out[45]
    DIRECTION OUTPUT ;
    USE SIGNAL ;
    SHAPE ABUTMENT ;
    PORT
      LAYER met3 ;
      RECT 0.000 497.760 0.300 498.060 ;
    END
  END rd_out[45]
  PIN rd_out[46]
    DIRECTION OUTPUT ;
    USE SIGNAL ;
    SHAPE ABUTMENT ;
    PORT
      LAYER met3 ;
      RECT 0.000 500.480 0.300 500.780 ;
    END
  END rd_out[46]
  PIN rd_out[47]
    DIRECTION OUTPUT ;
    USE SIGNAL ;
    SHAPE ABUTMENT ;
    PORT
      LAYER met3 ;
      RECT 0.000 503.200 0.300 503.500 ;
    END
  END rd_out[47]
  PIN rd_out[48]
    DIRECTION OUTPUT ;
    USE SIGNAL ;
    SHAPE ABUTMENT ;
    PORT
      LAYER met3 ;
      RECT 0.000 505.920 0.300 506.220 ;
    END
  END rd_out[48]
  PIN rd_out[49]
    DIRECTION OUTPUT ;
    USE SIGNAL ;
    SHAPE ABUTMENT ;
    PORT
      LAYER met3 ;
      RECT 0.000 508.640 0.300 508.940 ;
    END
  END rd_out[49]
  PIN rd_out[50]
    DIRECTION OUTPUT ;
    USE SIGNAL ;
    SHAPE ABUTMENT ;
    PORT
      LAYER met3 ;
      RECT 0.000 511.360 0.300 511.660 ;
    END
  END rd_out[50]
  PIN rd_out[51]
    DIRECTION OUTPUT ;
    USE SIGNAL ;
    SHAPE ABUTMENT ;
    PORT
      LAYER met3 ;
      RECT 0.000 514.080 0.300 514.380 ;
    END
  END rd_out[51]
  PIN rd_out[52]
    DIRECTION OUTPUT ;
    USE SIGNAL ;
    SHAPE ABUTMENT ;
    PORT
      LAYER met3 ;
      RECT 0.000 516.800 0.300 517.100 ;
    END
  END rd_out[52]
  PIN rd_out[53]
    DIRECTION OUTPUT ;
    USE SIGNAL ;
    SHAPE ABUTMENT ;
    PORT
      LAYER met3 ;
      RECT 0.000 519.520 0.300 519.820 ;
    END
  END rd_out[53]
  PIN rd_out[54]
    DIRECTION OUTPUT ;
    USE SIGNAL ;
    SHAPE ABUTMENT ;
    PORT
      LAYER met3 ;
      RECT 0.000 522.240 0.300 522.540 ;
    END
  END rd_out[54]
  PIN rd_out[55]
    DIRECTION OUTPUT ;
    USE SIGNAL ;
    SHAPE ABUTMENT ;
    PORT
      LAYER met3 ;
      RECT 0.000 524.960 0.300 525.260 ;
    END
  END rd_out[55]
  PIN rd_out[56]
    DIRECTION OUTPUT ;
    USE SIGNAL ;
    SHAPE ABUTMENT ;
    PORT
      LAYER met3 ;
      RECT 0.000 527.680 0.300 527.980 ;
    END
  END rd_out[56]
  PIN rd_out[57]
    DIRECTION OUTPUT ;
    USE SIGNAL ;
    SHAPE ABUTMENT ;
    PORT
      LAYER met3 ;
      RECT 0.000 530.400 0.300 530.700 ;
    END
  END rd_out[57]
  PIN rd_out[58]
    DIRECTION OUTPUT ;
    USE SIGNAL ;
    SHAPE ABUTMENT ;
    PORT
      LAYER met3 ;
      RECT 0.000 533.120 0.300 533.420 ;
    END
  END rd_out[58]
  PIN rd_out[59]
    DIRECTION OUTPUT ;
    USE SIGNAL ;
    SHAPE ABUTMENT ;
    PORT
      LAYER met3 ;
      RECT 0.000 535.840 0.300 536.140 ;
    END
  END rd_out[59]
  PIN rd_out[60]
    DIRECTION OUTPUT ;
    USE SIGNAL ;
    SHAPE ABUTMENT ;
    PORT
      LAYER met3 ;
      RECT 0.000 538.560 0.300 538.860 ;
    END
  END rd_out[60]
  PIN rd_out[61]
    DIRECTION OUTPUT ;
    USE SIGNAL ;
    SHAPE ABUTMENT ;
    PORT
      LAYER met3 ;
      RECT 0.000 541.280 0.300 541.580 ;
    END
  END rd_out[61]
  PIN rd_out[62]
    DIRECTION OUTPUT ;
    USE SIGNAL ;
    SHAPE ABUTMENT ;
    PORT
      LAYER met3 ;
      RECT 0.000 544.000 0.300 544.300 ;
    END
  END rd_out[62]
  PIN rd_out[63]
    DIRECTION OUTPUT ;
    USE SIGNAL ;
    SHAPE ABUTMENT ;
    PORT
      LAYER met3 ;
      RECT 0.000 546.720 0.300 547.020 ;
    END
  END rd_out[63]
  PIN clk
    DIRECTION INPUT ;
    USE SIGNAL ;
    SHAPE ABUTMENT ;
    PORT
      LAYER met3 ;
      RECT 0.000 549.440 0.300 549.740 ;
    END
  END clk
  PIN ce_in
    DIRECTION INPUT ;
    USE SIGNAL ;
    SHAPE ABUTMENT ;
    PORT
      LAYER met3 ;
      RECT 0.000 552.160 0.300 552.460 ;
    END
  END ce_in
  PIN we_in
    DIRECTION INPUT ;
    USE SIGNAL ;
    SHAPE ABUTMENT ;
    PORT
      LAYER met3 ;
      RECT 0.000 554.880 0.300 555.180 ;
    END
  END we_in
  OBS
    LAYER met1 ;
      RECT 0.000 0.000 809.600 565.760 ;
    LAYER met2 ;
      RECT 0.000 0.000 809.600 565.760 ;
    LAYER met3 ;
      RECT 0.000 0.000 809.600 565.760 ;
  END
END fakeram_512x64_1rw
END LIBRARY
